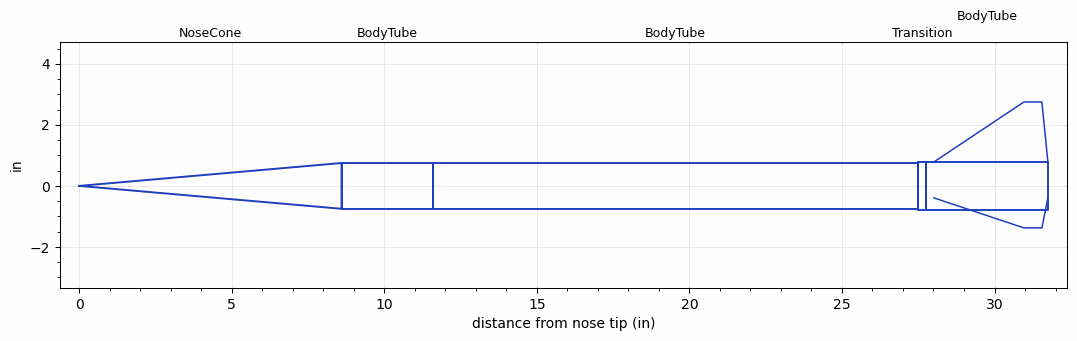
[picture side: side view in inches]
<RASAeroDocument>
 <FileVersion>2</FileVersion>
 <RocketDesign>
  <NoseCone>
   <Length>8.6</Length>
   <Diameter>1.5</Diameter>
   <Shape>Conical</Shape>
   <BluntRadius>0.065</BluntRadius>
   <Location>0</Location>
  </NoseCone>
  <BodyTube>
   <Length>3</Length>
   <Diameter>1.5</Diameter>
   <Location>8.6</Location>
  </BodyTube>
  <BodyTube>
   <Length>15.9</Length>
   <Diameter>1.5</Diameter>
   <Location>11.6</Location>
  </BodyTube>
  <Transition>
   <Length>0.25</Length>
   <Diameter>1.565</Diameter>
   <Location>27.5</Location>
   <RearDiameter>1.565</RearDiameter>
  </Transition>
  <BodyTube>
   <Length>4</Length>
   <Diameter>1.565</Diameter>
   <Location>27.75</Location>
   <Fin>
    <Count>3</Count>
    <Chord>3.7401</Chord>
    <Span>1.9685</Span>
    <SweepDistance>2.9527</SweepDistance>
    <TipChord>0.5905</TipChord>
    <Thickness>0.0906</Thickness>
    <LERadius>0.02</LERadius>
    <Location>3.7401</Location>
    <AirfoilSection>Hexagonal</AirfoilSection>
    <FX1>0.25</FX1>
    <FX3>0.25</FX3>
   </Fin>
  </BodyTube>
  <Surface>Rough Camouflage Paint</Surface>
  <ModifiedBarrowman>True</ModifiedBarrowman>
  <Turbulence>True</Turbulence>
  <UseBooster1>False</UseBooster1>
  <UseBooster2>False</UseBooster2>
 </RocketDesign>
 <LaunchSite>
  <Altitude>2000</Altitude>
  <Pressure>27.83</Pressure>
  <RodAngle>0</RodAngle>
  <RodLength>5</RodLength>
  <Temperature>51.87</Temperature>
  <WindSpeed>4.47</WindSpeed>
 </LaunchSite>
 <Recovery>
  <Altitude1>0</Altitude1>
  <Altitude2>0</Altitude2>
  <DeviceType1>None</DeviceType1>
  <DeviceType2>None</DeviceType2>
  <Event1>False</Event1>
  <Event2>False</Event2>
  <Size1>0</Size1>
  <Size2>0</Size2>
  <EventType1>None</EventType1>
  <EventType2>None</EventType2>
  <CD1>0</CD1>
  <CD2>0</CD2>
 </Recovery>
 <SimulationList>
  <Simulation>
   <SustainerEngine>J1250HLBL  (Polaris)</SustainerEngine>
   <SustainerLaunchWt>2.44</SustainerLaunchWt>
   <SustainerCG>20.95</SustainerCG>
   <SustainerIgnitionDelay>0</SustainerIgnitionDelay>
   <Booster1SeparationDelay>0</Booster1SeparationDelay>
   <Booster1IgnitionDelay>0</Booster1IgnitionDelay>
   <IncludeBooster1>False</IncludeBooster1>
   <Booster2Delay>0</Booster2Delay>
   <IncludeBooster2>False</IncludeBooster2>
   <TimetoApogee>22.01041</TimetoApogee>
   <MaxAltitude>13681.15</MaxAltitude>
   <MaxVelocity>3185.35</MaxVelocity>
  </Simulation>
 </SimulationList>
</RASAeroDocument>
